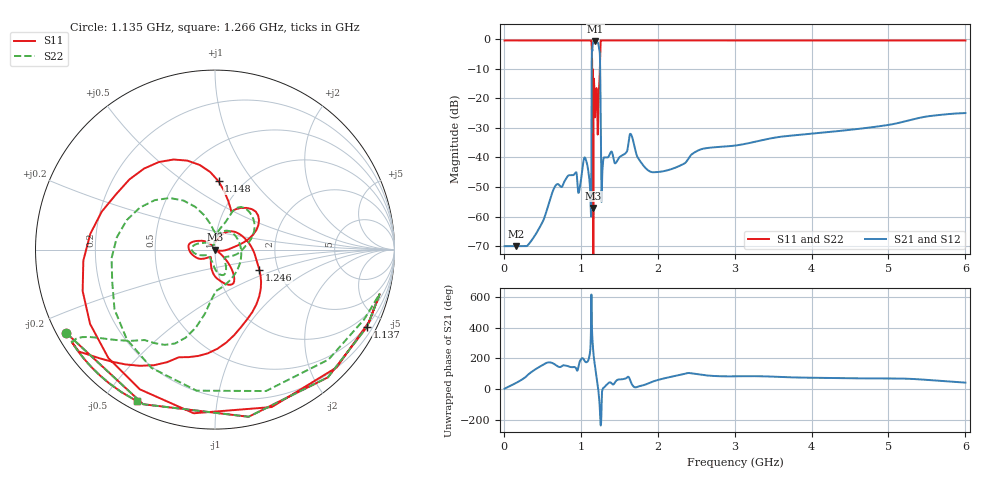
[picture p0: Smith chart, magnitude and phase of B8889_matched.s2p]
! Project 16: GNSS L1 + L2/L5 active antenna front end (RFMW-ANT)
! Generated by Scripts/simulate.py from Scripts/ds_data.py; format GHz / RI, Z0 = 50 ohm
! ESTIMATED from Qualcomm RF360 B8889 (B39122B8889P810) data sheet v2.1, 9 Apr 2019, INCLUDING the required 6.8 nH shunt inductors at
! both ports (datasheet curves are measured with them). Do not add Lp1/Lp4 again.
! Method as B7504.s2p. NOT measured data.
# GHz S RI R 50.0
!freq ReS11 ImS11 ReS21 ImS21 ReS12 ImS12 ReS22 ImS22
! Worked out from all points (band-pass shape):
!   11981 points, 10 MHz to 6 GHz, reference 50 ohm
!   highest |S21| = -0.75 dB at 1.19 GHz (marker M1); lowest = -70.0 dB at 155 MHz (marker M2)
!   |S21| within 3 dB of the highest: 1.14717 GHz to 1.1495 GHz (2.33 MHz wide, 0.203 % of centre); 1.151 GHz to 1.244 GHz (93.17 MHz wide, 7.78 % of centre)
!   lowest |S11| = -57.1 dB at 1.163 GHz (marker M3), VSWR 1.00, Z = 50.1 - j0.0593 ohm
!   |S11| at or under -10 dB: 1.149 GHz to 1.248 GHz (98.94 MHz wide, 8.26 % of centre)
!   |S22| runs from -32.3 to -0.4 dB; largest |S21 - S12| = 0
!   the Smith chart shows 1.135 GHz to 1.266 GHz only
!   S11 on the Smith chart (normalised r, x): 1.135 GHz: 0.03, -0.26; 1.137 GHz: 0.47, -4.12; 1.148 GHz: 0.77, +0.69; 1.246 GHz: 1.60, -0.39; 1.266 GHz: 0.04, -0.61
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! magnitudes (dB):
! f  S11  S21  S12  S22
! 10 MHz  -0.4  -70.0  -70.0  -0.4
! 155 MHz  -0.4  -70.0  -70.0  -0.4
! 387 MHz  -0.4  -67.1  -67.1  -0.4
! 677.5 MHz  -0.4  -49.3  -49.3  -0.4
! 1.008 GHz  -0.4  -46.5  -46.5  -0.4
! 1.06 GHz  -0.4  -40.3  -40.3  -0.4
! 1.108 GHz  -0.4  -46.6  -46.6  -0.4
! 1.135 GHz  -0.4  -60.0  -60.0  -0.4
! 1.137 GHz  -0.4  -44.3  -44.3  -0.4
! 1.148 GHz  -8.4  -3.6  -3.6  -20.8
! 1.163 GHz  -57.1  -0.9  -0.9  -21.0
! 1.19 GHz  -22.6  -0.8  -0.8  -26.4
! 1.226 GHz  -27.8  -1.4  -1.4  -25.6
! 1.246 GHz  -11.3  -4.4  -4.4  -16.2
! 1.266 GHz  -0.4  -46.1  -46.1  -0.4
! 1.293 GHz  -0.4  -40.7  -40.7  -0.4
! 1.653 GHz  -0.4  -32.2  -32.2  -0.4
! 2.007 GHz  -0.4  -44.9  -44.9  -0.4
! 3.005 GHz  -0.4  -36.0  -36.0  -0.4
! 4.003 GHz  -0.4  -32.0  -32.0  -0.4
! 5.002 GHz  -0.5  -29.0  -29.0  -0.5
! 6 GHz  -0.5  -25.0  -25.0  -0.5
